VERSION 5.7 ;
  NOWIREEXTENSIONATPIN ON ;
  DIVIDERCHAR "/" ;
  BUSBITCHARS "[]" ;
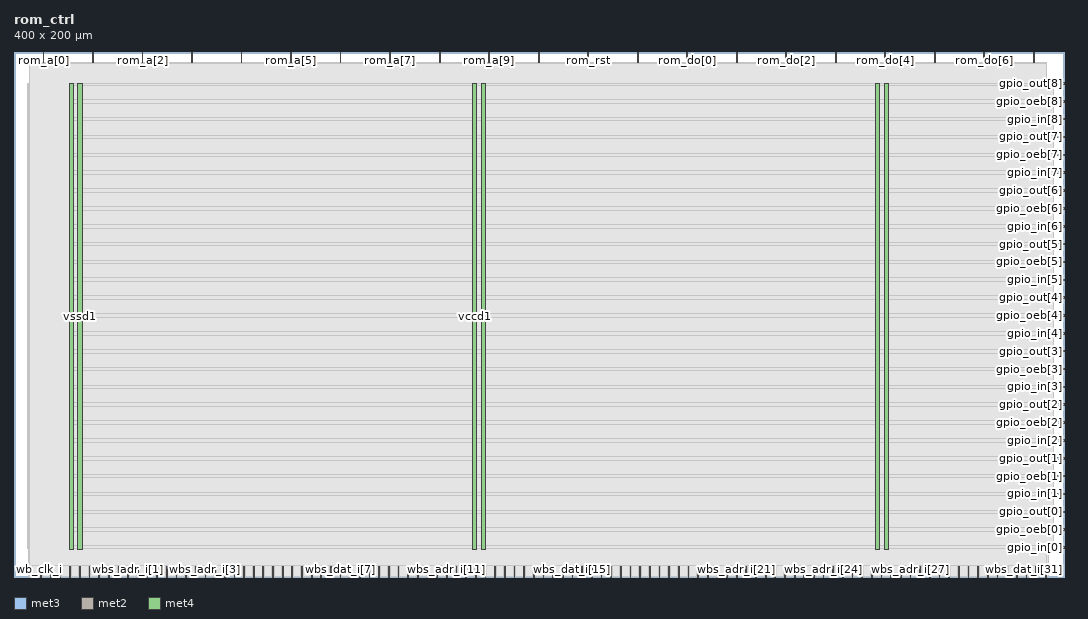
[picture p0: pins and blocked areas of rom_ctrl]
MACRO rom_ctrl
  CLASS BLOCK ;
  FOREIGN rom_ctrl ;
  ORIGIN 0.000 0.000 ;
  SIZE 400.000 BY 200.000 ;
  PIN gpio_in[0]
    DIRECTION INPUT ;
    USE SIGNAL ;
    PORT
      LAYER met3 ;
        RECT 396.000 10.920 400.000 11.520 ;
    END
  END gpio_in[0]
  PIN gpio_in[1]
    DIRECTION INPUT ;
    USE SIGNAL ;
    PORT
      LAYER met3 ;
        RECT 396.000 31.320 400.000 31.920 ;
    END
  END gpio_in[1]
  PIN gpio_in[2]
    DIRECTION INPUT ;
    USE SIGNAL ;
    PORT
      LAYER met3 ;
        RECT 396.000 51.720 400.000 52.320 ;
    END
  END gpio_in[2]
  PIN gpio_in[3]
    DIRECTION INPUT ;
    USE SIGNAL ;
    ANTENNAGATEAREA 0.631200 ;
    ANTENNADIFFAREA 0.434700 ;
    PORT
      LAYER met3 ;
        RECT 396.000 72.120 400.000 72.720 ;
    END
  END gpio_in[3]
  PIN gpio_in[4]
    DIRECTION INPUT ;
    USE SIGNAL ;
    ANTENNAGATEAREA 0.631200 ;
    ANTENNADIFFAREA 0.434700 ;
    PORT
      LAYER met3 ;
        RECT 396.000 92.520 400.000 93.120 ;
    END
  END gpio_in[4]
  PIN gpio_in[5]
    DIRECTION INPUT ;
    USE SIGNAL ;
    ANTENNAGATEAREA 0.631200 ;
    ANTENNADIFFAREA 0.434700 ;
    PORT
      LAYER met3 ;
        RECT 396.000 112.920 400.000 113.520 ;
    END
  END gpio_in[5]
  PIN gpio_in[6]
    DIRECTION INPUT ;
    USE SIGNAL ;
    ANTENNAGATEAREA 0.631200 ;
    ANTENNADIFFAREA 0.434700 ;
    PORT
      LAYER met3 ;
        RECT 396.000 133.320 400.000 133.920 ;
    END
  END gpio_in[6]
  PIN gpio_in[7]
    DIRECTION INPUT ;
    USE SIGNAL ;
    PORT
      LAYER met3 ;
        RECT 396.000 153.720 400.000 154.320 ;
    END
  END gpio_in[7]
  PIN gpio_in[8]
    DIRECTION INPUT ;
    USE SIGNAL ;
    PORT
      LAYER met3 ;
        RECT 396.000 174.120 400.000 174.720 ;
    END
  END gpio_in[8]
  PIN gpio_oeb[0]
    DIRECTION OUTPUT ;
    USE SIGNAL ;
    PORT
      LAYER met3 ;
        RECT 396.000 17.720 400.000 18.320 ;
    END
  END gpio_oeb[0]
  PIN gpio_oeb[1]
    DIRECTION OUTPUT ;
    USE SIGNAL ;
    PORT
      LAYER met3 ;
        RECT 396.000 38.120 400.000 38.720 ;
    END
  END gpio_oeb[1]
  PIN gpio_oeb[2]
    DIRECTION OUTPUT ;
    USE SIGNAL ;
    PORT
      LAYER met3 ;
        RECT 396.000 58.520 400.000 59.120 ;
    END
  END gpio_oeb[2]
  PIN gpio_oeb[3]
    DIRECTION OUTPUT ;
    USE SIGNAL ;
    PORT
      LAYER met3 ;
        RECT 396.000 78.920 400.000 79.520 ;
    END
  END gpio_oeb[3]
  PIN gpio_oeb[4]
    DIRECTION OUTPUT ;
    USE SIGNAL ;
    PORT
      LAYER met3 ;
        RECT 396.000 99.320 400.000 99.920 ;
    END
  END gpio_oeb[4]
  PIN gpio_oeb[5]
    DIRECTION OUTPUT ;
    USE SIGNAL ;
    PORT
      LAYER met3 ;
        RECT 396.000 119.720 400.000 120.320 ;
    END
  END gpio_oeb[5]
  PIN gpio_oeb[6]
    DIRECTION OUTPUT ;
    USE SIGNAL ;
    PORT
      LAYER met3 ;
        RECT 396.000 140.120 400.000 140.720 ;
    END
  END gpio_oeb[6]
  PIN gpio_oeb[7]
    DIRECTION OUTPUT ;
    USE SIGNAL ;
    ANTENNADIFFAREA 2.673000 ;
    PORT
      LAYER met3 ;
        RECT 396.000 160.520 400.000 161.120 ;
    END
  END gpio_oeb[7]
  PIN gpio_oeb[8]
    DIRECTION OUTPUT ;
    USE SIGNAL ;
    PORT
      LAYER met3 ;
        RECT 396.000 180.920 400.000 181.520 ;
    END
  END gpio_oeb[8]
  PIN gpio_out[0]
    DIRECTION OUTPUT ;
    USE SIGNAL ;
    ANTENNADIFFAREA 2.673000 ;
    PORT
      LAYER met3 ;
        RECT 396.000 24.520 400.000 25.120 ;
    END
  END gpio_out[0]
  PIN gpio_out[1]
    DIRECTION OUTPUT ;
    USE SIGNAL ;
    ANTENNADIFFAREA 2.673000 ;
    PORT
      LAYER met3 ;
        RECT 396.000 44.920 400.000 45.520 ;
    END
  END gpio_out[1]
  PIN gpio_out[2]
    DIRECTION OUTPUT ;
    USE SIGNAL ;
    ANTENNADIFFAREA 2.673000 ;
    PORT
      LAYER met3 ;
        RECT 396.000 65.320 400.000 65.920 ;
    END
  END gpio_out[2]
  PIN gpio_out[3]
    DIRECTION OUTPUT ;
    USE SIGNAL ;
    PORT
      LAYER met3 ;
        RECT 396.000 85.720 400.000 86.320 ;
    END
  END gpio_out[3]
  PIN gpio_out[4]
    DIRECTION OUTPUT ;
    USE SIGNAL ;
    PORT
      LAYER met3 ;
        RECT 396.000 106.120 400.000 106.720 ;
    END
  END gpio_out[4]
  PIN gpio_out[5]
    DIRECTION OUTPUT ;
    USE SIGNAL ;
    PORT
      LAYER met3 ;
        RECT 396.000 126.520 400.000 127.120 ;
    END
  END gpio_out[5]
  PIN gpio_out[6]
    DIRECTION OUTPUT ;
    USE SIGNAL ;
    PORT
      LAYER met3 ;
        RECT 396.000 146.920 400.000 147.520 ;
    END
  END gpio_out[6]
  PIN gpio_out[7]
    DIRECTION OUTPUT ;
    USE SIGNAL ;
    ANTENNADIFFAREA 2.673000 ;
    PORT
      LAYER met3 ;
        RECT 396.000 167.320 400.000 167.920 ;
    END
  END gpio_out[7]
  PIN gpio_out[8]
    DIRECTION OUTPUT ;
    USE SIGNAL ;
    ANTENNADIFFAREA 2.673000 ;
    PORT
      LAYER met3 ;
        RECT 396.000 187.720 400.000 188.320 ;
    END
  END gpio_out[8]
  PIN rom_a[0]
    DIRECTION OUTPUT ;
    USE SIGNAL ;
    ANTENNADIFFAREA 2.673000 ;
    PORT
      LAYER met2 ;
        RECT 11.130 196.000 11.410 200.000 ;
    END
  END rom_a[0]
  PIN rom_a[1]
    DIRECTION OUTPUT ;
    USE SIGNAL ;
    ANTENNADIFFAREA 2.673000 ;
    PORT
      LAYER met2 ;
        RECT 29.990 196.000 30.270 200.000 ;
    END
  END rom_a[1]
  PIN rom_a[2]
    DIRECTION OUTPUT ;
    USE SIGNAL ;
    ANTENNADIFFAREA 2.673000 ;
    PORT
      LAYER met2 ;
        RECT 48.850 196.000 49.130 200.000 ;
    END
  END rom_a[2]
  PIN rom_a[3]
    DIRECTION OUTPUT ;
    USE SIGNAL ;
    ANTENNADIFFAREA 2.673000 ;
    PORT
      LAYER met2 ;
        RECT 67.710 196.000 67.990 200.000 ;
    END
  END rom_a[3]
  PIN rom_a[4]
    DIRECTION OUTPUT ;
    USE SIGNAL ;
    ANTENNADIFFAREA 2.673000 ;
    PORT
      LAYER met2 ;
        RECT 86.570 196.000 86.850 200.000 ;
    END
  END rom_a[4]
  PIN rom_a[5]
    DIRECTION OUTPUT ;
    USE SIGNAL ;
    ANTENNADIFFAREA 2.673000 ;
    PORT
      LAYER met2 ;
        RECT 105.430 196.000 105.710 200.000 ;
    END
  END rom_a[5]
  PIN rom_a[6]
    DIRECTION OUTPUT ;
    USE SIGNAL ;
    ANTENNADIFFAREA 2.673000 ;
    PORT
      LAYER met2 ;
        RECT 124.290 196.000 124.570 200.000 ;
    END
  END rom_a[6]
  PIN rom_a[7]
    DIRECTION OUTPUT ;
    USE SIGNAL ;
    ANTENNADIFFAREA 2.673000 ;
    PORT
      LAYER met2 ;
        RECT 143.150 196.000 143.430 200.000 ;
    END
  END rom_a[7]
  PIN rom_a[8]
    DIRECTION OUTPUT ;
    USE SIGNAL ;
    ANTENNADIFFAREA 2.673000 ;
    PORT
      LAYER met2 ;
        RECT 162.010 196.000 162.290 200.000 ;
    END
  END rom_a[8]
  PIN rom_a[9]
    DIRECTION OUTPUT ;
    USE SIGNAL ;
    ANTENNADIFFAREA 2.673000 ;
    PORT
      LAYER met2 ;
        RECT 180.870 196.000 181.150 200.000 ;
    END
  END rom_a[9]
  PIN rom_do[0]
    DIRECTION INPUT ;
    USE SIGNAL ;
    ANTENNAGATEAREA 0.631200 ;
    ANTENNADIFFAREA 0.434700 ;
    PORT
      LAYER met2 ;
        RECT 256.310 196.000 256.590 200.000 ;
    END
  END rom_do[0]
  PIN rom_do[1]
    DIRECTION INPUT ;
    USE SIGNAL ;
    ANTENNAGATEAREA 0.631200 ;
    ANTENNADIFFAREA 0.434700 ;
    PORT
      LAYER met2 ;
        RECT 275.170 196.000 275.450 200.000 ;
    END
  END rom_do[1]
  PIN rom_do[2]
    DIRECTION INPUT ;
    USE SIGNAL ;
    ANTENNAGATEAREA 0.631200 ;
    ANTENNADIFFAREA 0.434700 ;
    PORT
      LAYER met2 ;
        RECT 294.030 196.000 294.310 200.000 ;
    END
  END rom_do[2]
  PIN rom_do[3]
    DIRECTION INPUT ;
    USE SIGNAL ;
    ANTENNAGATEAREA 0.631200 ;
    ANTENNADIFFAREA 0.434700 ;
    PORT
      LAYER met2 ;
        RECT 312.890 196.000 313.170 200.000 ;
    END
  END rom_do[3]
  PIN rom_do[4]
    DIRECTION INPUT ;
    USE SIGNAL ;
    ANTENNAGATEAREA 0.631200 ;
    ANTENNADIFFAREA 0.434700 ;
    PORT
      LAYER met2 ;
        RECT 331.750 196.000 332.030 200.000 ;
    END
  END rom_do[4]
  PIN rom_do[5]
    DIRECTION INPUT ;
    USE SIGNAL ;
    ANTENNAGATEAREA 0.631200 ;
    ANTENNADIFFAREA 0.434700 ;
    PORT
      LAYER met2 ;
        RECT 350.610 196.000 350.890 200.000 ;
    END
  END rom_do[5]
  PIN rom_do[6]
    DIRECTION INPUT ;
    USE SIGNAL ;
    ANTENNAGATEAREA 0.631200 ;
    ANTENNADIFFAREA 0.434700 ;
    PORT
      LAYER met2 ;
        RECT 369.470 196.000 369.750 200.000 ;
    END
  END rom_do[6]
  PIN rom_do[7]
    DIRECTION INPUT ;
    USE SIGNAL ;
    ANTENNAGATEAREA 0.631200 ;
    ANTENNADIFFAREA 0.434700 ;
    PORT
      LAYER met2 ;
        RECT 388.330 196.000 388.610 200.000 ;
    END
  END rom_do[7]
  PIN rom_en
    DIRECTION OUTPUT ;
    USE SIGNAL ;
    ANTENNADIFFAREA 2.673000 ;
    PORT
      LAYER met2 ;
        RECT 199.730 196.000 200.010 200.000 ;
    END
  END rom_en
  PIN rom_oe
    DIRECTION OUTPUT ;
    USE SIGNAL ;
    ANTENNADIFFAREA 2.673000 ;
    PORT
      LAYER met2 ;
        RECT 237.450 196.000 237.730 200.000 ;
    END
  END rom_oe
  PIN rom_rst
    DIRECTION OUTPUT ;
    USE SIGNAL ;
    ANTENNADIFFAREA 2.673000 ;
    PORT
      LAYER met2 ;
        RECT 218.590 196.000 218.870 200.000 ;
    END
  END rom_rst
  PIN vccd1
    DIRECTION INOUT ;
    USE POWER ;
    PORT
      LAYER met4 ;
        RECT 21.040 10.640 22.640 187.920 ;
    END
    PORT
      LAYER met4 ;
        RECT 174.640 10.640 176.240 187.920 ;
    END
    PORT
      LAYER met4 ;
        RECT 328.240 10.640 329.840 187.920 ;
    END
  END vccd1
  PIN vssd1
    DIRECTION INOUT ;
    USE GROUND ;
    PORT
      LAYER met4 ;
        RECT 24.340 10.640 25.940 187.920 ;
    END
    PORT
      LAYER met4 ;
        RECT 177.940 10.640 179.540 187.920 ;
    END
    PORT
      LAYER met4 ;
        RECT 331.540 10.640 333.140 187.920 ;
    END
  END vssd1
  PIN wb_clk_i
    DIRECTION INPUT ;
    USE SIGNAL ;
    ANTENNAGATEAREA 1.286700 ;
    ANTENNADIFFAREA 0.434700 ;
    PORT
      LAYER met2 ;
        RECT 6.530 0.000 6.810 4.000 ;
    END
  END wb_clk_i
  PIN wb_rst_i
    DIRECTION INPUT ;
    USE SIGNAL ;
    ANTENNAGATEAREA 0.631200 ;
    ANTENNADIFFAREA 0.434700 ;
    PORT
      LAYER met2 ;
        RECT 10.210 0.000 10.490 4.000 ;
    END
  END wb_rst_i
  PIN wbs_ack_o
    DIRECTION OUTPUT ;
    USE SIGNAL ;
    ANTENNADIFFAREA 2.673000 ;
    PORT
      LAYER met2 ;
        RECT 13.890 0.000 14.170 4.000 ;
    END
  END wbs_ack_o
  PIN wbs_adr_i[0]
    DIRECTION INPUT ;
    USE SIGNAL ;
    ANTENNAGATEAREA 0.560700 ;
    ANTENNADIFFAREA 0.434700 ;
    PORT
      LAYER met2 ;
        RECT 28.610 0.000 28.890 4.000 ;
    END
  END wbs_adr_i[0]
  PIN wbs_adr_i[10]
    DIRECTION INPUT ;
    USE SIGNAL ;
    ANTENNAGATEAREA 0.560700 ;
    ANTENNADIFFAREA 0.434700 ;
    PORT
      LAYER met2 ;
        RECT 153.730 0.000 154.010 4.000 ;
    END
  END wbs_adr_i[10]
  PIN wbs_adr_i[11]
    DIRECTION INPUT ;
    USE SIGNAL ;
    ANTENNAGATEAREA 0.560700 ;
    ANTENNADIFFAREA 0.434700 ;
    PORT
      LAYER met2 ;
        RECT 164.770 0.000 165.050 4.000 ;
    END
  END wbs_adr_i[11]
  PIN wbs_adr_i[12]
    DIRECTION INPUT ;
    USE SIGNAL ;
    ANTENNAGATEAREA 0.560700 ;
    ANTENNADIFFAREA 0.434700 ;
    PORT
      LAYER met2 ;
        RECT 175.810 0.000 176.090 4.000 ;
    END
  END wbs_adr_i[12]
  PIN wbs_adr_i[13]
    DIRECTION INPUT ;
    USE SIGNAL ;
    ANTENNAGATEAREA 0.560700 ;
    ANTENNADIFFAREA 0.434700 ;
    PORT
      LAYER met2 ;
        RECT 186.850 0.000 187.130 4.000 ;
    END
  END wbs_adr_i[13]
  PIN wbs_adr_i[14]
    DIRECTION INPUT ;
    USE SIGNAL ;
    ANTENNAGATEAREA 0.631200 ;
    ANTENNADIFFAREA 0.434700 ;
    PORT
      LAYER met2 ;
        RECT 197.890 0.000 198.170 4.000 ;
    END
  END wbs_adr_i[14]
  PIN wbs_adr_i[15]
    DIRECTION INPUT ;
    USE SIGNAL ;
    ANTENNAGATEAREA 0.631200 ;
    ANTENNADIFFAREA 0.434700 ;
    PORT
      LAYER met2 ;
        RECT 208.930 0.000 209.210 4.000 ;
    END
  END wbs_adr_i[15]
  PIN wbs_adr_i[16]
    DIRECTION INPUT ;
    USE SIGNAL ;
    ANTENNAGATEAREA 0.631200 ;
    ANTENNADIFFAREA 0.434700 ;
    PORT
      LAYER met2 ;
        RECT 219.970 0.000 220.250 4.000 ;
    END
  END wbs_adr_i[16]
  PIN wbs_adr_i[17]
    DIRECTION INPUT ;
    USE SIGNAL ;
    ANTENNAGATEAREA 0.631200 ;
    ANTENNADIFFAREA 0.434700 ;
    PORT
      LAYER met2 ;
        RECT 231.010 0.000 231.290 4.000 ;
    END
  END wbs_adr_i[17]
  PIN wbs_adr_i[18]
    DIRECTION INPUT ;
    USE SIGNAL ;
    ANTENNAGATEAREA 0.631200 ;
    ANTENNADIFFAREA 0.434700 ;
    PORT
      LAYER met2 ;
        RECT 242.050 0.000 242.330 4.000 ;
    END
  END wbs_adr_i[18]
  PIN wbs_adr_i[19]
    DIRECTION INPUT ;
    USE SIGNAL ;
    ANTENNAGATEAREA 0.631200 ;
    ANTENNADIFFAREA 0.434700 ;
    PORT
      LAYER met2 ;
        RECT 253.090 0.000 253.370 4.000 ;
    END
  END wbs_adr_i[19]
  PIN wbs_adr_i[1]
    DIRECTION INPUT ;
    USE SIGNAL ;
    ANTENNAGATEAREA 0.560700 ;
    ANTENNADIFFAREA 0.434700 ;
    PORT
      LAYER met2 ;
        RECT 43.330 0.000 43.610 4.000 ;
    END
  END wbs_adr_i[1]
  PIN wbs_adr_i[20]
    DIRECTION INPUT ;
    USE SIGNAL ;
    ANTENNAGATEAREA 0.631200 ;
    ANTENNADIFFAREA 0.434700 ;
    PORT
      LAYER met2 ;
        RECT 264.130 0.000 264.410 4.000 ;
    END
  END wbs_adr_i[20]
  PIN wbs_adr_i[21]
    DIRECTION INPUT ;
    USE SIGNAL ;
    ANTENNAGATEAREA 0.631200 ;
    ANTENNADIFFAREA 0.434700 ;
    PORT
      LAYER met2 ;
        RECT 275.170 0.000 275.450 4.000 ;
    END
  END wbs_adr_i[21]
  PIN wbs_adr_i[22]
    DIRECTION INPUT ;
    USE SIGNAL ;
    ANTENNAGATEAREA 0.560700 ;
    ANTENNADIFFAREA 0.434700 ;
    PORT
      LAYER met2 ;
        RECT 286.210 0.000 286.490 4.000 ;
    END
  END wbs_adr_i[22]
  PIN wbs_adr_i[23]
    DIRECTION INPUT ;
    USE SIGNAL ;
    ANTENNAGATEAREA 0.631200 ;
    ANTENNADIFFAREA 0.434700 ;
    PORT
      LAYER met2 ;
        RECT 297.250 0.000 297.530 4.000 ;
    END
  END wbs_adr_i[23]
  PIN wbs_adr_i[24]
    DIRECTION INPUT ;
    USE SIGNAL ;
    ANTENNAGATEAREA 0.631200 ;
    ANTENNADIFFAREA 0.434700 ;
    PORT
      LAYER met2 ;
        RECT 308.290 0.000 308.570 4.000 ;
    END
  END wbs_adr_i[24]
  PIN wbs_adr_i[25]
    DIRECTION INPUT ;
    USE SIGNAL ;
    ANTENNAGATEAREA 0.631200 ;
    ANTENNADIFFAREA 0.434700 ;
    PORT
      LAYER met2 ;
        RECT 319.330 0.000 319.610 4.000 ;
    END
  END wbs_adr_i[25]
  PIN wbs_adr_i[26]
    DIRECTION INPUT ;
    USE SIGNAL ;
    ANTENNAGATEAREA 0.631200 ;
    ANTENNADIFFAREA 0.434700 ;
    PORT
      LAYER met2 ;
        RECT 330.370 0.000 330.650 4.000 ;
    END
  END wbs_adr_i[26]
  PIN wbs_adr_i[27]
    DIRECTION INPUT ;
    USE SIGNAL ;
    ANTENNAGATEAREA 0.631200 ;
    ANTENNADIFFAREA 0.434700 ;
    PORT
      LAYER met2 ;
        RECT 341.410 0.000 341.690 4.000 ;
    END
  END wbs_adr_i[27]
  PIN wbs_adr_i[28]
    DIRECTION INPUT ;
    USE SIGNAL ;
    ANTENNAGATEAREA 0.631200 ;
    ANTENNADIFFAREA 0.434700 ;
    PORT
      LAYER met2 ;
        RECT 352.450 0.000 352.730 4.000 ;
    END
  END wbs_adr_i[28]
  PIN wbs_adr_i[29]
    DIRECTION INPUT ;
    USE SIGNAL ;
    ANTENNAGATEAREA 0.631200 ;
    ANTENNADIFFAREA 0.434700 ;
    PORT
      LAYER met2 ;
        RECT 363.490 0.000 363.770 4.000 ;
    END
  END wbs_adr_i[29]
  PIN wbs_adr_i[2]
    DIRECTION INPUT ;
    USE SIGNAL ;
    ANTENNAGATEAREA 0.560700 ;
    ANTENNADIFFAREA 0.434700 ;
    PORT
      LAYER met2 ;
        RECT 58.050 0.000 58.330 4.000 ;
    END
  END wbs_adr_i[2]
  PIN wbs_adr_i[30]
    DIRECTION INPUT ;
    USE SIGNAL ;
    ANTENNAGATEAREA 0.631200 ;
    ANTENNADIFFAREA 0.434700 ;
    PORT
      LAYER met2 ;
        RECT 374.530 0.000 374.810 4.000 ;
    END
  END wbs_adr_i[30]
  PIN wbs_adr_i[31]
    DIRECTION INPUT ;
    USE SIGNAL ;
    ANTENNAGATEAREA 0.631200 ;
    ANTENNADIFFAREA 0.434700 ;
    PORT
      LAYER met2 ;
        RECT 385.570 0.000 385.850 4.000 ;
    END
  END wbs_adr_i[31]
  PIN wbs_adr_i[3]
    DIRECTION INPUT ;
    USE SIGNAL ;
    ANTENNAGATEAREA 0.560700 ;
    ANTENNADIFFAREA 0.434700 ;
    PORT
      LAYER met2 ;
        RECT 72.770 0.000 73.050 4.000 ;
    END
  END wbs_adr_i[3]
  PIN wbs_adr_i[4]
    DIRECTION INPUT ;
    USE SIGNAL ;
    ANTENNAGATEAREA 0.560700 ;
    ANTENNADIFFAREA 0.434700 ;
    PORT
      LAYER met2 ;
        RECT 87.490 0.000 87.770 4.000 ;
    END
  END wbs_adr_i[4]
  PIN wbs_adr_i[5]
    DIRECTION INPUT ;
    USE SIGNAL ;
    ANTENNAGATEAREA 0.560700 ;
    ANTENNADIFFAREA 0.434700 ;
    PORT
      LAYER met2 ;
        RECT 98.530 0.000 98.810 4.000 ;
    END
  END wbs_adr_i[5]
  PIN wbs_adr_i[6]
    DIRECTION INPUT ;
    USE SIGNAL ;
    ANTENNAGATEAREA 0.560700 ;
    ANTENNADIFFAREA 0.434700 ;
    PORT
      LAYER met2 ;
        RECT 109.570 0.000 109.850 4.000 ;
    END
  END wbs_adr_i[6]
  PIN wbs_adr_i[7]
    DIRECTION INPUT ;
    USE SIGNAL ;
    ANTENNAGATEAREA 0.560700 ;
    ANTENNADIFFAREA 0.434700 ;
    PORT
      LAYER met2 ;
        RECT 120.610 0.000 120.890 4.000 ;
    END
  END wbs_adr_i[7]
  PIN wbs_adr_i[8]
    DIRECTION INPUT ;
    USE SIGNAL ;
    ANTENNAGATEAREA 0.560700 ;
    ANTENNADIFFAREA 0.434700 ;
    PORT
      LAYER met2 ;
        RECT 131.650 0.000 131.930 4.000 ;
    END
  END wbs_adr_i[8]
  PIN wbs_adr_i[9]
    DIRECTION INPUT ;
    USE SIGNAL ;
    ANTENNAGATEAREA 0.560700 ;
    ANTENNADIFFAREA 0.434700 ;
    PORT
      LAYER met2 ;
        RECT 142.690 0.000 142.970 4.000 ;
    END
  END wbs_adr_i[9]
  PIN wbs_cyc_i
    DIRECTION INPUT ;
    USE SIGNAL ;
    ANTENNAGATEAREA 0.631200 ;
    ANTENNADIFFAREA 0.434700 ;
    PORT
      LAYER met2 ;
        RECT 17.570 0.000 17.850 4.000 ;
    END
  END wbs_cyc_i
  PIN wbs_dat_i[0]
    DIRECTION INPUT ;
    USE SIGNAL ;
    ANTENNAGATEAREA 0.560700 ;
    ANTENNADIFFAREA 0.434700 ;
    PORT
      LAYER met2 ;
        RECT 32.290 0.000 32.570 4.000 ;
    END
  END wbs_dat_i[0]
  PIN wbs_dat_i[10]
    DIRECTION INPUT ;
    USE SIGNAL ;
    ANTENNAGATEAREA 0.560700 ;
    ANTENNADIFFAREA 0.434700 ;
    PORT
      LAYER met2 ;
        RECT 157.410 0.000 157.690 4.000 ;
    END
  END wbs_dat_i[10]
  PIN wbs_dat_i[11]
    DIRECTION INPUT ;
    USE SIGNAL ;
    ANTENNAGATEAREA 0.560700 ;
    ANTENNADIFFAREA 0.434700 ;
    PORT
      LAYER met2 ;
        RECT 168.450 0.000 168.730 4.000 ;
    END
  END wbs_dat_i[11]
  PIN wbs_dat_i[12]
    DIRECTION INPUT ;
    USE SIGNAL ;
    ANTENNAGATEAREA 0.560700 ;
    ANTENNADIFFAREA 0.434700 ;
    PORT
      LAYER met2 ;
        RECT 179.490 0.000 179.770 4.000 ;
    END
  END wbs_dat_i[12]
  PIN wbs_dat_i[13]
    DIRECTION INPUT ;
    USE SIGNAL ;
    ANTENNAGATEAREA 0.560700 ;
    ANTENNADIFFAREA 0.434700 ;
    PORT
      LAYER met2 ;
        RECT 190.530 0.000 190.810 4.000 ;
    END
  END wbs_dat_i[13]
  PIN wbs_dat_i[14]
    DIRECTION INPUT ;
    USE SIGNAL ;
    ANTENNAGATEAREA 0.560700 ;
    ANTENNADIFFAREA 0.434700 ;
    PORT
      LAYER met2 ;
        RECT 201.570 0.000 201.850 4.000 ;
    END
  END wbs_dat_i[14]
  PIN wbs_dat_i[15]
    DIRECTION INPUT ;
    USE SIGNAL ;
    ANTENNAGATEAREA 0.560700 ;
    ANTENNADIFFAREA 0.434700 ;
    PORT
      LAYER met2 ;
        RECT 212.610 0.000 212.890 4.000 ;
    END
  END wbs_dat_i[15]
  PIN wbs_dat_i[16]
    DIRECTION INPUT ;
    USE SIGNAL ;
    ANTENNAGATEAREA 0.560700 ;
    ANTENNADIFFAREA 0.434700 ;
    PORT
      LAYER met2 ;
        RECT 223.650 0.000 223.930 4.000 ;
    END
  END wbs_dat_i[16]
  PIN wbs_dat_i[17]
    DIRECTION INPUT ;
    USE SIGNAL ;
    PORT
      LAYER met2 ;
        RECT 234.690 0.000 234.970 4.000 ;
    END
  END wbs_dat_i[17]
  PIN wbs_dat_i[18]
    DIRECTION INPUT ;
    USE SIGNAL ;
    PORT
      LAYER met2 ;
        RECT 245.730 0.000 246.010 4.000 ;
    END
  END wbs_dat_i[18]
  PIN wbs_dat_i[19]
    DIRECTION INPUT ;
    USE SIGNAL ;
    PORT
      LAYER met2 ;
        RECT 256.770 0.000 257.050 4.000 ;
    END
  END wbs_dat_i[19]
  PIN wbs_dat_i[1]
    DIRECTION INPUT ;
    USE SIGNAL ;
    ANTENNAGATEAREA 0.560700 ;
    ANTENNADIFFAREA 0.434700 ;
    PORT
      LAYER met2 ;
        RECT 47.010 0.000 47.290 4.000 ;
    END
  END wbs_dat_i[1]
  PIN wbs_dat_i[20]
    DIRECTION INPUT ;
    USE SIGNAL ;
    PORT
      LAYER met2 ;
        RECT 267.810 0.000 268.090 4.000 ;
    END
  END wbs_dat_i[20]
  PIN wbs_dat_i[21]
    DIRECTION INPUT ;
    USE SIGNAL ;
    PORT
      LAYER met2 ;
        RECT 278.850 0.000 279.130 4.000 ;
    END
  END wbs_dat_i[21]
  PIN wbs_dat_i[22]
    DIRECTION INPUT ;
    USE SIGNAL ;
    PORT
      LAYER met2 ;
        RECT 289.890 0.000 290.170 4.000 ;
    END
  END wbs_dat_i[22]
  PIN wbs_dat_i[23]
    DIRECTION INPUT ;
    USE SIGNAL ;
    PORT
      LAYER met2 ;
        RECT 300.930 0.000 301.210 4.000 ;
    END
  END wbs_dat_i[23]
  PIN wbs_dat_i[24]
    DIRECTION INPUT ;
    USE SIGNAL ;
    PORT
      LAYER met2 ;
        RECT 311.970 0.000 312.250 4.000 ;
    END
  END wbs_dat_i[24]
  PIN wbs_dat_i[25]
    DIRECTION INPUT ;
    USE SIGNAL ;
    PORT
      LAYER met2 ;
        RECT 323.010 0.000 323.290 4.000 ;
    END
  END wbs_dat_i[25]
  PIN wbs_dat_i[26]
    DIRECTION INPUT ;
    USE SIGNAL ;
    PORT
      LAYER met2 ;
        RECT 334.050 0.000 334.330 4.000 ;
    END
  END wbs_dat_i[26]
  PIN wbs_dat_i[27]
    DIRECTION INPUT ;
    USE SIGNAL ;
    PORT
      LAYER met2 ;
        RECT 345.090 0.000 345.370 4.000 ;
    END
  END wbs_dat_i[27]
  PIN wbs_dat_i[28]
    DIRECTION INPUT ;
    USE SIGNAL ;
    PORT
      LAYER met2 ;
        RECT 356.130 0.000 356.410 4.000 ;
    END
  END wbs_dat_i[28]
  PIN wbs_dat_i[29]
    DIRECTION INPUT ;
    USE SIGNAL ;
    PORT
      LAYER met2 ;
        RECT 367.170 0.000 367.450 4.000 ;
    END
  END wbs_dat_i[29]
  PIN wbs_dat_i[2]
    DIRECTION INPUT ;
    USE SIGNAL ;
    ANTENNAGATEAREA 0.560700 ;
    ANTENNADIFFAREA 0.434700 ;
    PORT
      LAYER met2 ;
        RECT 61.730 0.000 62.010 4.000 ;
    END
  END wbs_dat_i[2]
  PIN wbs_dat_i[30]
    DIRECTION INPUT ;
    USE SIGNAL ;
    PORT
      LAYER met2 ;
        RECT 378.210 0.000 378.490 4.000 ;
    END
  END wbs_dat_i[30]
  PIN wbs_dat_i[31]
    DIRECTION INPUT ;
    USE SIGNAL ;
    PORT
      LAYER met2 ;
        RECT 389.250 0.000 389.530 4.000 ;
    END
  END wbs_dat_i[31]
  PIN wbs_dat_i[3]
    DIRECTION INPUT ;
    USE SIGNAL ;
    ANTENNAGATEAREA 0.560700 ;
    ANTENNADIFFAREA 0.434700 ;
    PORT
      LAYER met2 ;
        RECT 76.450 0.000 76.730 4.000 ;
    END
  END wbs_dat_i[3]
  PIN wbs_dat_i[4]
    DIRECTION INPUT ;
    USE SIGNAL ;
    ANTENNAGATEAREA 0.560700 ;
    ANTENNADIFFAREA 0.434700 ;
    PORT
      LAYER met2 ;
        RECT 91.170 0.000 91.450 4.000 ;
    END
  END wbs_dat_i[4]
  PIN wbs_dat_i[5]
    DIRECTION INPUT ;
    USE SIGNAL ;
    ANTENNAGATEAREA 0.560700 ;
    ANTENNADIFFAREA 0.434700 ;
    PORT
      LAYER met2 ;
        RECT 102.210 0.000 102.490 4.000 ;
    END
  END wbs_dat_i[5]
  PIN wbs_dat_i[6]
    DIRECTION INPUT ;
    USE SIGNAL ;
    ANTENNAGATEAREA 0.560700 ;
    ANTENNADIFFAREA 0.434700 ;
    PORT
      LAYER met2 ;
        RECT 113.250 0.000 113.530 4.000 ;
    END
  END wbs_dat_i[6]
  PIN wbs_dat_i[7]
    DIRECTION INPUT ;
    USE SIGNAL ;
    ANTENNAGATEAREA 0.560700 ;
    ANTENNADIFFAREA 0.434700 ;
    PORT
      LAYER met2 ;
        RECT 124.290 0.000 124.570 4.000 ;
    END
  END wbs_dat_i[7]
  PIN wbs_dat_i[8]
    DIRECTION INPUT ;
    USE SIGNAL ;
    ANTENNAGATEAREA 0.560700 ;
    ANTENNADIFFAREA 0.434700 ;
    PORT
      LAYER met2 ;
        RECT 135.330 0.000 135.610 4.000 ;
    END
  END wbs_dat_i[8]
  PIN wbs_dat_i[9]
    DIRECTION INPUT ;
    USE SIGNAL ;
    ANTENNAGATEAREA 0.560700 ;
    ANTENNADIFFAREA 0.434700 ;
    PORT
      LAYER met2 ;
        RECT 146.370 0.000 146.650 4.000 ;
    END
  END wbs_dat_i[9]
  PIN wbs_dat_o[0]
    DIRECTION OUTPUT ;
    USE SIGNAL ;
    ANTENNADIFFAREA 2.673000 ;
    PORT
      LAYER met2 ;
        RECT 35.970 0.000 36.250 4.000 ;
    END
  END wbs_dat_o[0]
  PIN wbs_dat_o[10]
    DIRECTION OUTPUT ;
    USE SIGNAL ;
    ANTENNADIFFAREA 2.673000 ;
    PORT
      LAYER met2 ;
        RECT 161.090 0.000 161.370 4.000 ;
    END
  END wbs_dat_o[10]
  PIN wbs_dat_o[11]
    DIRECTION OUTPUT ;
    USE SIGNAL ;
    ANTENNADIFFAREA 2.673000 ;
    PORT
      LAYER met2 ;
        RECT 172.130 0.000 172.410 4.000 ;
    END
  END wbs_dat_o[11]
  PIN wbs_dat_o[12]
    DIRECTION OUTPUT ;
    USE SIGNAL ;
    ANTENNADIFFAREA 2.673000 ;
    PORT
      LAYER met2 ;
        RECT 183.170 0.000 183.450 4.000 ;
    END
  END wbs_dat_o[12]
  PIN wbs_dat_o[13]
    DIRECTION OUTPUT ;
    USE SIGNAL ;
    ANTENNADIFFAREA 2.673000 ;
    PORT
      LAYER met2 ;
        RECT 194.210 0.000 194.490 4.000 ;
    END
  END wbs_dat_o[13]
  PIN wbs_dat_o[14]
    DIRECTION OUTPUT ;
    USE SIGNAL ;
    ANTENNADIFFAREA 2.673000 ;
    PORT
      LAYER met2 ;
        RECT 205.250 0.000 205.530 4.000 ;
    END
  END wbs_dat_o[14]
  PIN wbs_dat_o[15]
    DIRECTION OUTPUT ;
    USE SIGNAL ;
    ANTENNADIFFAREA 2.673000 ;
    PORT
      LAYER met2 ;
        RECT 216.290 0.000 216.570 4.000 ;
    END
  END wbs_dat_o[15]
  PIN wbs_dat_o[16]
    DIRECTION OUTPUT ;
    USE SIGNAL ;
    ANTENNADIFFAREA 2.673000 ;
    PORT
      LAYER met2 ;
        RECT 227.330 0.000 227.610 4.000 ;
    END
  END wbs_dat_o[16]
  PIN wbs_dat_o[17]
    DIRECTION OUTPUT ;
    USE SIGNAL ;
    ANTENNADIFFAREA 2.673000 ;
    PORT
      LAYER met2 ;
        RECT 238.370 0.000 238.650 4.000 ;
    END
  END wbs_dat_o[17]
  PIN wbs_dat_o[18]
    DIRECTION OUTPUT ;
    USE SIGNAL ;
    ANTENNADIFFAREA 2.673000 ;
    PORT
      LAYER met2 ;
        RECT 249.410 0.000 249.690 4.000 ;
    END
  END wbs_dat_o[18]
  PIN wbs_dat_o[19]
    DIRECTION OUTPUT ;
    USE SIGNAL ;
    ANTENNADIFFAREA 2.673000 ;
    PORT
      LAYER met2 ;
        RECT 260.450 0.000 260.730 4.000 ;
    END
  END wbs_dat_o[19]
  PIN wbs_dat_o[1]
    DIRECTION OUTPUT ;
    USE SIGNAL ;
    ANTENNADIFFAREA 2.673000 ;
    PORT
      LAYER met2 ;
        RECT 50.690 0.000 50.970 4.000 ;
    END
  END wbs_dat_o[1]
  PIN wbs_dat_o[20]
    DIRECTION OUTPUT ;
    USE SIGNAL ;
    ANTENNADIFFAREA 2.673000 ;
    PORT
      LAYER met2 ;
        RECT 271.490 0.000 271.770 4.000 ;
    END
  END wbs_dat_o[20]
  PIN wbs_dat_o[21]
    DIRECTION OUTPUT ;
    USE SIGNAL ;
    ANTENNADIFFAREA 2.673000 ;
    PORT
      LAYER met2 ;
        RECT 282.530 0.000 282.810 4.000 ;
    END
  END wbs_dat_o[21]
  PIN wbs_dat_o[22]
    DIRECTION OUTPUT ;
    USE SIGNAL ;
    ANTENNADIFFAREA 2.673000 ;
    PORT
      LAYER met2 ;
        RECT 293.570 0.000 293.850 4.000 ;
    END
  END wbs_dat_o[22]
  PIN wbs_dat_o[23]
    DIRECTION OUTPUT ;
    USE SIGNAL ;
    ANTENNADIFFAREA 2.673000 ;
    PORT
      LAYER met2 ;
        RECT 304.610 0.000 304.890 4.000 ;
    END
  END wbs_dat_o[23]
  PIN wbs_dat_o[24]
    DIRECTION OUTPUT ;
    USE SIGNAL ;
    ANTENNADIFFAREA 2.673000 ;
    PORT
      LAYER met2 ;
        RECT 315.650 0.000 315.930 4.000 ;
    END
  END wbs_dat_o[24]
  PIN wbs_dat_o[25]
    DIRECTION OUTPUT ;
    USE SIGNAL ;
    ANTENNADIFFAREA 2.673000 ;
    PORT
      LAYER met2 ;
        RECT 326.690 0.000 326.970 4.000 ;
    END
  END wbs_dat_o[25]
  PIN wbs_dat_o[26]
    DIRECTION OUTPUT ;
    USE SIGNAL ;
    ANTENNADIFFAREA 2.673000 ;
    PORT
      LAYER met2 ;
        RECT 337.730 0.000 338.010 4.000 ;
    END
  END wbs_dat_o[26]
  PIN wbs_dat_o[27]
    DIRECTION OUTPUT ;
    USE SIGNAL ;
    ANTENNADIFFAREA 2.673000 ;
    PORT
      LAYER met2 ;
        RECT 348.770 0.000 349.050 4.000 ;
    END
  END wbs_dat_o[27]
  PIN wbs_dat_o[28]
    DIRECTION OUTPUT ;
    USE SIGNAL ;
    ANTENNADIFFAREA 2.673000 ;
    PORT
      LAYER met2 ;
        RECT 359.810 0.000 360.090 4.000 ;
    END
  END wbs_dat_o[28]
  PIN wbs_dat_o[29]
    DIRECTION OUTPUT ;
    USE SIGNAL ;
    ANTENNADIFFAREA 2.673000 ;
    PORT
      LAYER met2 ;
        RECT 370.850 0.000 371.130 4.000 ;
    END
  END wbs_dat_o[29]
  PIN wbs_dat_o[2]
    DIRECTION OUTPUT ;
    USE SIGNAL ;
    ANTENNADIFFAREA 2.673000 ;
    PORT
      LAYER met2 ;
        RECT 65.410 0.000 65.690 4.000 ;
    END
  END wbs_dat_o[2]
  PIN wbs_dat_o[30]
    DIRECTION OUTPUT ;
    USE SIGNAL ;
    ANTENNADIFFAREA 2.673000 ;
    PORT
      LAYER met2 ;
        RECT 381.890 0.000 382.170 4.000 ;
    END
  END wbs_dat_o[30]
  PIN wbs_dat_o[31]
    DIRECTION OUTPUT ;
    USE SIGNAL ;
    ANTENNADIFFAREA 2.673000 ;
    PORT
      LAYER met2 ;
        RECT 392.930 0.000 393.210 4.000 ;
    END
  END wbs_dat_o[31]
  PIN wbs_dat_o[3]
    DIRECTION OUTPUT ;
    USE SIGNAL ;
    ANTENNADIFFAREA 2.673000 ;
    PORT
      LAYER met2 ;
        RECT 80.130 0.000 80.410 4.000 ;
    END
  END wbs_dat_o[3]
  PIN wbs_dat_o[4]
    DIRECTION OUTPUT ;
    USE SIGNAL ;
    ANTENNADIFFAREA 2.673000 ;
    PORT
      LAYER met2 ;
        RECT 94.850 0.000 95.130 4.000 ;
    END
  END wbs_dat_o[4]
  PIN wbs_dat_o[5]
    DIRECTION OUTPUT ;
    USE SIGNAL ;
    ANTENNADIFFAREA 2.673000 ;
    PORT
      LAYER met2 ;
        RECT 105.890 0.000 106.170 4.000 ;
    END
  END wbs_dat_o[5]
  PIN wbs_dat_o[6]
    DIRECTION OUTPUT ;
    USE SIGNAL ;
    ANTENNADIFFAREA 2.673000 ;
    PORT
      LAYER met2 ;
        RECT 116.930 0.000 117.210 4.000 ;
    END
  END wbs_dat_o[6]
  PIN wbs_dat_o[7]
    DIRECTION OUTPUT ;
    USE SIGNAL ;
    ANTENNADIFFAREA 2.673000 ;
    PORT
      LAYER met2 ;
        RECT 127.970 0.000 128.250 4.000 ;
    END
  END wbs_dat_o[7]
  PIN wbs_dat_o[8]
    DIRECTION OUTPUT ;
    USE SIGNAL ;
    ANTENNADIFFAREA 2.673000 ;
    PORT
      LAYER met2 ;
        RECT 139.010 0.000 139.290 4.000 ;
    END
  END wbs_dat_o[8]
  PIN wbs_dat_o[9]
    DIRECTION OUTPUT ;
    USE SIGNAL ;
    ANTENNADIFFAREA 2.673000 ;
    PORT
      LAYER met2 ;
        RECT 150.050 0.000 150.330 4.000 ;
    END
  END wbs_dat_o[9]
  PIN wbs_sel_i[0]
    DIRECTION INPUT ;
    USE SIGNAL ;
    ANTENNAGATEAREA 0.560700 ;
    ANTENNADIFFAREA 0.434700 ;
    PORT
      LAYER met2 ;
        RECT 39.650 0.000 39.930 4.000 ;
    END
  END wbs_sel_i[0]
  PIN wbs_sel_i[1]
    DIRECTION INPUT ;
    USE SIGNAL ;
    ANTENNAGATEAREA 0.560700 ;
    ANTENNADIFFAREA 0.434700 ;
    PORT
      LAYER met2 ;
        RECT 54.370 0.000 54.650 4.000 ;
    END
  END wbs_sel_i[1]
  PIN wbs_sel_i[2]
    DIRECTION INPUT ;
    USE SIGNAL ;
    ANTENNAGATEAREA 0.560700 ;
    ANTENNADIFFAREA 0.434700 ;
    PORT
      LAYER met2 ;
        RECT 69.090 0.000 69.370 4.000 ;
    END
  END wbs_sel_i[2]
  PIN wbs_sel_i[3]
    DIRECTION INPUT ;
    USE SIGNAL ;
    ANTENNAGATEAREA 0.560700 ;
    ANTENNADIFFAREA 0.434700 ;
    PORT
      LAYER met2 ;
        RECT 83.810 0.000 84.090 4.000 ;
    END
  END wbs_sel_i[3]
  PIN wbs_stb_i
    DIRECTION INPUT ;
    USE SIGNAL ;
    ANTENNAGATEAREA 0.647700 ;
    ANTENNADIFFAREA 0.434700 ;
    PORT
      LAYER met2 ;
        RECT 21.250 0.000 21.530 4.000 ;
    END
  END wbs_stb_i
  PIN wbs_we_i
    DIRECTION INPUT ;
    USE SIGNAL ;
    ANTENNAGATEAREA 0.631200 ;
    ANTENNADIFFAREA 0.434700 ;
    PORT
      LAYER met2 ;
        RECT 24.930 0.000 25.210 4.000 ;
    END
  END wbs_we_i
  OBS
      LAYER nwell ;
        RECT 5.330 10.760 394.410 187.870 ;
      LAYER li1 ;
        RECT 5.520 10.795 394.220 187.765 ;
      LAYER met1 ;
        RECT 5.520 0.380 394.220 187.920 ;
      LAYER met2 ;
        RECT 6.080 195.720 10.850 196.000 ;
        RECT 11.690 195.720 29.710 196.000 ;
        RECT 30.550 195.720 48.570 196.000 ;
        RECT 49.410 195.720 67.430 196.000 ;
        RECT 68.270 195.720 86.290 196.000 ;
        RECT 87.130 195.720 105.150 196.000 ;
        RECT 105.990 195.720 124.010 196.000 ;
        RECT 124.850 195.720 142.870 196.000 ;
        RECT 143.710 195.720 161.730 196.000 ;
        RECT 162.570 195.720 180.590 196.000 ;
        RECT 181.430 195.720 199.450 196.000 ;
        RECT 200.290 195.720 218.310 196.000 ;
        RECT 219.150 195.720 237.170 196.000 ;
        RECT 238.010 195.720 256.030 196.000 ;
        RECT 256.870 195.720 274.890 196.000 ;
        RECT 275.730 195.720 293.750 196.000 ;
        RECT 294.590 195.720 312.610 196.000 ;
        RECT 313.450 195.720 331.470 196.000 ;
        RECT 332.310 195.720 350.330 196.000 ;
        RECT 351.170 195.720 369.190 196.000 ;
        RECT 370.030 195.720 388.050 196.000 ;
        RECT 388.890 195.720 393.200 196.000 ;
        RECT 6.080 4.280 393.200 195.720 ;
        RECT 6.080 0.350 6.250 4.280 ;
        RECT 7.090 0.350 9.930 4.280 ;
        RECT 10.770 0.350 13.610 4.280 ;
        RECT 14.450 0.350 17.290 4.280 ;
        RECT 18.130 0.350 20.970 4.280 ;
        RECT 21.810 0.350 24.650 4.280 ;
        RECT 25.490 0.350 28.330 4.280 ;
        RECT 29.170 0.350 32.010 4.280 ;
        RECT 32.850 0.350 35.690 4.280 ;
        RECT 36.530 0.350 39.370 4.280 ;
        RECT 40.210 0.350 43.050 4.280 ;
        RECT 43.890 0.350 46.730 4.280 ;
        RECT 47.570 0.350 50.410 4.280 ;
        RECT 51.250 0.350 54.090 4.280 ;
        RECT 54.930 0.350 57.770 4.280 ;
        RECT 58.610 0.350 61.450 4.280 ;
        RECT 62.290 0.350 65.130 4.280 ;
        RECT 65.970 0.350 68.810 4.280 ;
        RECT 69.650 0.350 72.490 4.280 ;
        RECT 73.330 0.350 76.170 4.280 ;
        RECT 77.010 0.350 79.850 4.280 ;
        RECT 80.690 0.350 83.530 4.280 ;
        RECT 84.370 0.350 87.210 4.280 ;
        RECT 88.050 0.350 90.890 4.280 ;
        RECT 91.730 0.350 94.570 4.280 ;
        RECT 95.410 0.350 98.250 4.280 ;
        RECT 99.090 0.350 101.930 4.280 ;
        RECT 102.770 0.350 105.610 4.280 ;
        RECT 106.450 0.350 109.290 4.280 ;
        RECT 110.130 0.350 112.970 4.280 ;
        RECT 113.810 0.350 116.650 4.280 ;
        RECT 117.490 0.350 120.330 4.280 ;
        RECT 121.170 0.350 124.010 4.280 ;
        RECT 124.850 0.350 127.690 4.280 ;
        RECT 128.530 0.350 131.370 4.280 ;
        RECT 132.210 0.350 135.050 4.280 ;
        RECT 135.890 0.350 138.730 4.280 ;
        RECT 139.570 0.350 142.410 4.280 ;
        RECT 143.250 0.350 146.090 4.280 ;
        RECT 146.930 0.350 149.770 4.280 ;
        RECT 150.610 0.350 153.450 4.280 ;
        RECT 154.290 0.350 157.130 4.280 ;
        RECT 157.970 0.350 160.810 4.280 ;
        RECT 161.650 0.350 164.490 4.280 ;
        RECT 165.330 0.350 168.170 4.280 ;
        RECT 169.010 0.350 171.850 4.280 ;
        RECT 172.690 0.350 175.530 4.280 ;
        RECT 176.370 0.350 179.210 4.280 ;
        RECT 180.050 0.350 182.890 4.280 ;
        RECT 183.730 0.350 186.570 4.280 ;
        RECT 187.410 0.350 190.250 4.280 ;
        RECT 191.090 0.350 193.930 4.280 ;
        RECT 194.770 0.350 197.610 4.280 ;
        RECT 198.450 0.350 201.290 4.280 ;
        RECT 202.130 0.350 204.970 4.280 ;
        RECT 205.810 0.350 208.650 4.280 ;
        RECT 209.490 0.350 212.330 4.280 ;
        RECT 213.170 0.350 216.010 4.280 ;
        RECT 216.850 0.350 219.690 4.280 ;
        RECT 220.530 0.350 223.370 4.280 ;
        RECT 224.210 0.350 227.050 4.280 ;
        RECT 227.890 0.350 230.730 4.280 ;
        RECT 231.570 0.350 234.410 4.280 ;
        RECT 235.250 0.350 238.090 4.280 ;
        RECT 238.930 0.350 241.770 4.280 ;
        RECT 242.610 0.350 245.450 4.280 ;
        RECT 246.290 0.350 249.130 4.280 ;
        RECT 249.970 0.350 252.810 4.280 ;
        RECT 253.650 0.350 256.490 4.280 ;
        RECT 257.330 0.350 260.170 4.280 ;
        RECT 261.010 0.350 263.850 4.280 ;
        RECT 264.690 0.350 267.530 4.280 ;
        RECT 268.370 0.350 271.210 4.280 ;
        RECT 272.050 0.350 274.890 4.280 ;
        RECT 275.730 0.350 278.570 4.280 ;
        RECT 279.410 0.350 282.250 4.280 ;
        RECT 283.090 0.350 285.930 4.280 ;
        RECT 286.770 0.350 289.610 4.280 ;
        RECT 290.450 0.350 293.290 4.280 ;
        RECT 294.130 0.350 296.970 4.280 ;
        RECT 297.810 0.350 300.650 4.280 ;
        RECT 301.490 0.350 304.330 4.280 ;
        RECT 305.170 0.350 308.010 4.280 ;
        RECT 308.850 0.350 311.690 4.280 ;
        RECT 312.530 0.350 315.370 4.280 ;
        RECT 316.210 0.350 319.050 4.280 ;
        RECT 319.890 0.350 322.730 4.280 ;
        RECT 323.570 0.350 326.410 4.280 ;
        RECT 327.250 0.350 330.090 4.280 ;
        RECT 330.930 0.350 333.770 4.280 ;
        RECT 334.610 0.350 337.450 4.280 ;
        RECT 338.290 0.350 341.130 4.280 ;
        RECT 341.970 0.350 344.810 4.280 ;
        RECT 345.650 0.350 348.490 4.280 ;
        RECT 349.330 0.350 352.170 4.280 ;
        RECT 353.010 0.350 355.850 4.280 ;
        RECT 356.690 0.350 359.530 4.280 ;
        RECT 360.370 0.350 363.210 4.280 ;
        RECT 364.050 0.350 366.890 4.280 ;
        RECT 367.730 0.350 370.570 4.280 ;
        RECT 371.410 0.350 374.250 4.280 ;
        RECT 375.090 0.350 377.930 4.280 ;
        RECT 378.770 0.350 381.610 4.280 ;
        RECT 382.450 0.350 385.290 4.280 ;
        RECT 386.130 0.350 388.970 4.280 ;
        RECT 389.810 0.350 392.650 4.280 ;
      LAYER met3 ;
        RECT 21.050 187.320 395.600 188.185 ;
        RECT 21.050 181.920 396.000 187.320 ;
        RECT 21.050 180.520 395.600 181.920 ;
        RECT 21.050 175.120 396.000 180.520 ;
        RECT 21.050 173.720 395.600 175.120 ;
        RECT 21.050 168.320 396.000 173.720 ;
        RECT 21.050 166.920 395.600 168.320 ;
        RECT 21.050 161.520 396.000 166.920 ;
        RECT 21.050 160.120 395.600 161.520 ;
        RECT 21.050 154.720 396.000 160.120 ;
        RECT 21.050 153.320 395.600 154.720 ;
        RECT 21.050 147.920 396.000 153.320 ;
        RECT 21.050 146.520 395.600 147.920 ;
        RECT 21.050 141.120 396.000 146.520 ;
        RECT 21.050 139.720 395.600 141.120 ;
        RECT 21.050 134.320 396.000 139.720 ;
        RECT 21.050 132.920 395.600 134.320 ;
        RECT 21.050 127.520 396.000 132.920 ;
        RECT 21.050 126.120 395.600 127.520 ;
        RECT 21.050 120.720 396.000 126.120 ;
        RECT 21.050 119.320 395.600 120.720 ;
        RECT 21.050 113.920 396.000 119.320 ;
        RECT 21.050 112.520 395.600 113.920 ;
        RECT 21.050 107.120 396.000 112.520 ;
        RECT 21.050 105.720 395.600 107.120 ;
        RECT 21.050 100.320 396.000 105.720 ;
        RECT 21.050 98.920 395.600 100.320 ;
        RECT 21.050 93.520 396.000 98.920 ;
        RECT 21.050 92.120 395.600 93.520 ;
        RECT 21.050 86.720 396.000 92.120 ;
        RECT 21.050 85.320 395.600 86.720 ;
        RECT 21.050 79.920 396.000 85.320 ;
        RECT 21.050 78.520 395.600 79.920 ;
        RECT 21.050 73.120 396.000 78.520 ;
        RECT 21.050 71.720 395.600 73.120 ;
        RECT 21.050 66.320 396.000 71.720 ;
        RECT 21.050 64.920 395.600 66.320 ;
        RECT 21.050 59.520 396.000 64.920 ;
        RECT 21.050 58.120 395.600 59.520 ;
        RECT 21.050 52.720 396.000 58.120 ;
        RECT 21.050 51.320 395.600 52.720 ;
        RECT 21.050 45.920 396.000 51.320 ;
        RECT 21.050 44.520 395.600 45.920 ;
        RECT 21.050 39.120 396.000 44.520 ;
        RECT 21.050 37.720 395.600 39.120 ;
        RECT 21.050 32.320 396.000 37.720 ;
        RECT 21.050 30.920 395.600 32.320 ;
        RECT 21.050 25.520 396.000 30.920 ;
        RECT 21.050 24.120 395.600 25.520 ;
        RECT 21.050 18.720 396.000 24.120 ;
        RECT 21.050 17.320 395.600 18.720 ;
        RECT 21.050 11.920 396.000 17.320 ;
        RECT 21.050 10.715 395.600 11.920 ;
  END
END rom_ctrl
END LIBRARY

